VERSION 5.8 ;
BUSBITCHARS "[]" ;
DIVIDERCHAR "/" ;
UNITS
 DATABASE MICRONS 1000 ;
END UNITS
LAYER M1
 TYPE ROUTING ;
 DIRECTION HORIZONTAL ;
 PITCH 0.2 ;
 WIDTH 0.1 ;
END M1
SITE site
 CLASS CORE ;
 SIZE 1 BY 1 ;
END site
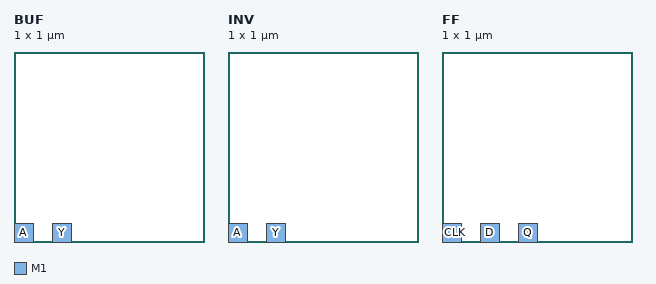
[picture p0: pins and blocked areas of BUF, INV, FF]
MACRO BUF
 CLASS CORE ;
 SIZE 1 BY 1 ;
 SITE site ;
 PIN A
  DIRECTION INPUT ;
  USE SIGNAL ;
  PORT
   LAYER M1 ;
   RECT 0.0 0.0 0.1 0.1 ;
  END
 END A
 PIN Y
  DIRECTION OUTPUT ;
  USE SIGNAL ;
  PORT
   LAYER M1 ;
   RECT 0.2 0.0 0.3 0.1 ;
  END
 END Y
END BUF
MACRO INV
 CLASS CORE ;
 SIZE 1 BY 1 ;
 SITE site ;
 PIN A
  DIRECTION INPUT ;
  USE SIGNAL ;
  PORT
   LAYER M1 ;
   RECT 0.0 0.0 0.1 0.1 ;
  END
 END A
 PIN Y
  DIRECTION OUTPUT ;
  USE SIGNAL ;
  PORT
   LAYER M1 ;
   RECT 0.2 0.0 0.3 0.1 ;
  END
 END Y
END INV
MACRO FF
 CLASS CORE ;
 SIZE 1 BY 1 ;
 SITE site ;
 PIN CLK
  DIRECTION INPUT ;
  USE CLOCK ;
  PORT
   LAYER M1 ;
   RECT 0.0 0.0 0.1 0.1 ;
  END
 END CLK
 PIN D
  DIRECTION INPUT ;
  USE SIGNAL ;
  PORT
   LAYER M1 ;
   RECT 0.2 0.0 0.3 0.1 ;
  END
 END D
 PIN Q
  DIRECTION OUTPUT ;
  USE SIGNAL ;
  PORT
   LAYER M1 ;
   RECT 0.4 0.0 0.5 0.1 ;
  END
 END Q
END FF
END LIBRARY
